VERSION 5.7 ;
  NOWIREEXTENSIONATPIN ON ;
  DIVIDERCHAR "/" ;
  BUSBITCHARS "[]" ;
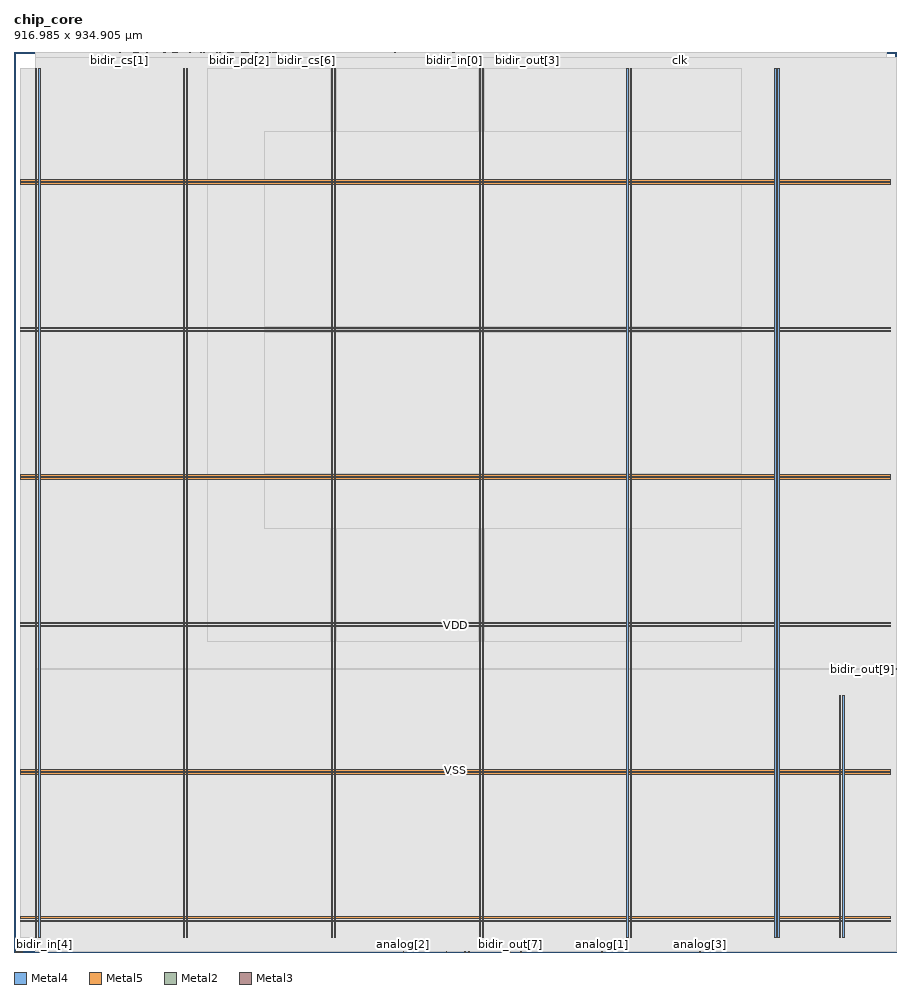
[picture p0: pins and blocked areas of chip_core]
MACRO chip_core
  CLASS BLOCK ;
  FOREIGN chip_core ;
  ORIGIN 0.000 0.000 ;
  SIZE 916.985 BY 934.905 ;
  PIN VDD
    DIRECTION INOUT ;
    USE POWER ;
    PORT
      LAYER Metal4 ;
        RECT 22.240 15.380 23.840 917.580 ;
    END
    PORT
      LAYER Metal4 ;
        RECT 175.840 15.380 177.440 917.580 ;
    END
    PORT
      LAYER Metal4 ;
        RECT 329.440 15.380 331.040 917.580 ;
    END
    PORT
      LAYER Metal4 ;
        RECT 483.040 15.380 484.640 917.580 ;
    END
    PORT
      LAYER Metal4 ;
        RECT 636.640 15.380 638.240 917.580 ;
    END
    PORT
      LAYER Metal4 ;
        RECT 790.240 15.380 791.840 917.580 ;
    END
    PORT
      LAYER Metal5 ;
        RECT 6.720 31.530 910.000 33.130 ;
    END
    PORT
      LAYER Metal5 ;
        RECT 6.720 184.710 910.000 186.310 ;
    END
    PORT
      LAYER Metal5 ;
        RECT 6.720 337.890 910.000 339.490 ;
    END
    PORT
      LAYER Metal5 ;
        RECT 6.720 491.070 910.000 492.670 ;
    END
    PORT
      LAYER Metal5 ;
        RECT 6.720 644.250 910.000 645.850 ;
    END
    PORT
      LAYER Metal5 ;
        RECT 6.720 797.430 910.000 799.030 ;
    END
    PORT
      LAYER Metal4 ;
        RECT 857.400 15.380 859.000 266.860 ;
    END
  END VDD
  PIN VSS
    DIRECTION INOUT ;
    USE GROUND ;
    PORT
      LAYER Metal4 ;
        RECT 25.540 15.380 27.140 917.580 ;
    END
    PORT
      LAYER Metal4 ;
        RECT 179.140 15.380 180.740 917.580 ;
    END
    PORT
      LAYER Metal4 ;
        RECT 332.740 15.380 334.340 917.580 ;
    END
    PORT
      LAYER Metal4 ;
        RECT 486.340 15.380 487.940 917.580 ;
    END
    PORT
      LAYER Metal4 ;
        RECT 639.940 15.380 641.540 917.580 ;
    END
    PORT
      LAYER Metal4 ;
        RECT 793.540 15.380 795.140 917.580 ;
    END
    PORT
      LAYER Metal5 ;
        RECT 6.720 34.830 910.000 36.430 ;
    END
    PORT
      LAYER Metal5 ;
        RECT 6.720 188.010 910.000 189.610 ;
    END
    PORT
      LAYER Metal5 ;
        RECT 6.720 341.190 910.000 342.790 ;
    END
    PORT
      LAYER Metal5 ;
        RECT 6.720 494.370 910.000 495.970 ;
    END
    PORT
      LAYER Metal5 ;
        RECT 6.720 647.550 910.000 649.150 ;
    END
    PORT
      LAYER Metal5 ;
        RECT 6.720 800.730 910.000 802.330 ;
    END
    PORT
      LAYER Metal4 ;
        RECT 860.760 15.380 862.360 266.860 ;
    END
  END VSS
  PIN analog[0]
    DIRECTION INOUT ;
    USE SIGNAL ;
    ANTENNAGATEAREA 0.741000 ;
    PORT
      LAYER Metal2 ;
        RECT 507.360 0.000 507.920 0.560 ;
    END
  END analog[0]
  PIN analog[1]
    DIRECTION INOUT ;
    USE SIGNAL ;
    ANTENNAGATEAREA 0.741000 ;
    PORT
      LAYER Metal2 ;
        RECT 610.400 0.000 610.960 0.560 ;
    END
  END analog[1]
  PIN analog[2]
    DIRECTION INOUT ;
    USE SIGNAL ;
    PORT
      LAYER Metal2 ;
        RECT 404.320 0.000 404.880 0.560 ;
    END
  END analog[2]
  PIN analog[3]
    DIRECTION INOUT ;
    USE SIGNAL ;
    ANTENNAGATEAREA 0.741000 ;
    PORT
      LAYER Metal2 ;
        RECT 712.320 0.000 712.880 0.560 ;
    END
  END analog[3]
  PIN bidir_cs[0]
    DIRECTION OUTPUT ;
    USE SIGNAL ;
    ANTENNADIFFAREA 0.536800 ;
    PORT
      LAYER Metal2 ;
        RECT 125.440 934.345 126.000 934.905 ;
    END
  END bidir_cs[0]
  PIN bidir_cs[1]
    DIRECTION OUTPUT ;
    USE SIGNAL ;
    ANTENNADIFFAREA 0.536800 ;
    PORT
      LAYER Metal2 ;
        RECT 109.760 934.345 110.320 934.905 ;
    END
  END bidir_cs[1]
  PIN bidir_cs[2]
    DIRECTION OUTPUT ;
    USE SIGNAL ;
    ANTENNADIFFAREA 0.536800 ;
    PORT
      LAYER Metal2 ;
        RECT 133.280 934.345 133.840 934.905 ;
    END
  END bidir_cs[2]
  PIN bidir_cs[3]
    DIRECTION OUTPUT ;
    USE SIGNAL ;
    ANTENNADIFFAREA 0.360800 ;
    PORT
      LAYER Metal2 ;
        RECT 229.600 934.345 230.160 934.905 ;
    END
  END bidir_cs[3]
  PIN bidir_cs[4]
    DIRECTION OUTPUT ;
    USE SIGNAL ;
    ANTENNADIFFAREA 0.360800 ;
    PORT
      LAYER Metal2 ;
        RECT 231.840 934.345 232.400 934.905 ;
    END
  END bidir_cs[4]
  PIN bidir_cs[5]
    DIRECTION OUTPUT ;
    USE SIGNAL ;
    ANTENNADIFFAREA 0.360800 ;
    PORT
      LAYER Metal2 ;
        RECT 155.680 934.345 156.240 934.905 ;
    END
  END bidir_cs[5]
  PIN bidir_cs[6]
    DIRECTION OUTPUT ;
    USE SIGNAL ;
    ANTENNADIFFAREA 0.360800 ;
    PORT
      LAYER Metal2 ;
        RECT 303.520 934.345 304.080 934.905 ;
    END
  END bidir_cs[6]
  PIN bidir_cs[7]
    DIRECTION OUTPUT ;
    USE SIGNAL ;
    ANTENNADIFFAREA 0.360800 ;
    PORT
      LAYER Metal2 ;
        RECT 131.040 934.345 131.600 934.905 ;
    END
  END bidir_cs[7]
  PIN bidir_cs[8]
    DIRECTION OUTPUT ;
    USE SIGNAL ;
    ANTENNADIFFAREA 0.360800 ;
    PORT
      LAYER Metal2 ;
        RECT 226.240 934.345 226.800 934.905 ;
    END
  END bidir_cs[8]
  PIN bidir_cs[9]
    DIRECTION OUTPUT ;
    USE SIGNAL ;
    ANTENNADIFFAREA 0.360800 ;
    PORT
      LAYER Metal2 ;
        RECT 241.920 934.345 242.480 934.905 ;
    END
  END bidir_cs[9]
  PIN bidir_ie[0]
    DIRECTION OUTPUT ;
    USE SIGNAL ;
    ANTENNADIFFAREA 0.536800 ;
    PORT
      LAYER Metal2 ;
        RECT 265.440 934.345 266.000 934.905 ;
    END
  END bidir_ie[0]
  PIN bidir_ie[1]
    DIRECTION OUTPUT ;
    USE SIGNAL ;
    ANTENNADIFFAREA 0.536800 ;
    PORT
      LAYER Metal2 ;
        RECT 169.120 934.345 169.680 934.905 ;
    END
  END bidir_ie[1]
  PIN bidir_ie[2]
    DIRECTION OUTPUT ;
    USE SIGNAL ;
    ANTENNADIFFAREA 0.536800 ;
    PORT
      LAYER Metal2 ;
        RECT 213.920 934.345 214.480 934.905 ;
    END
  END bidir_ie[2]
  PIN bidir_ie[3]
    DIRECTION OUTPUT ;
    USE SIGNAL ;
    ANTENNADIFFAREA 0.360800 ;
    PORT
      LAYER Metal2 ;
        RECT 236.320 934.345 236.880 934.905 ;
    END
  END bidir_ie[3]
  PIN bidir_ie[4]
    DIRECTION OUTPUT ;
    USE SIGNAL ;
    ANTENNADIFFAREA 0.360800 ;
    PORT
      LAYER Metal2 ;
        RECT 232.960 934.345 233.520 934.905 ;
    END
  END bidir_ie[4]
  PIN bidir_ie[5]
    DIRECTION OUTPUT ;
    USE SIGNAL ;
    ANTENNADIFFAREA 0.360800 ;
    PORT
      LAYER Metal2 ;
        RECT 197.120 934.345 197.680 934.905 ;
    END
  END bidir_ie[5]
  PIN bidir_ie[6]
    DIRECTION OUTPUT ;
    USE SIGNAL ;
    ANTENNADIFFAREA 0.360800 ;
    PORT
      LAYER Metal2 ;
        RECT 161.280 934.345 161.840 934.905 ;
    END
  END bidir_ie[6]
  PIN bidir_ie[7]
    DIRECTION OUTPUT ;
    USE SIGNAL ;
    ANTENNADIFFAREA 0.360800 ;
    PORT
      LAYER Metal2 ;
        RECT 235.200 934.345 235.760 934.905 ;
    END
  END bidir_ie[7]
  PIN bidir_ie[8]
    DIRECTION OUTPUT ;
    USE SIGNAL ;
    ANTENNADIFFAREA 0.360800 ;
    PORT
      LAYER Metal2 ;
        RECT 268.800 934.345 269.360 934.905 ;
    END
  END bidir_ie[8]
  PIN bidir_ie[9]
    DIRECTION OUTPUT ;
    USE SIGNAL ;
    ANTENNADIFFAREA 0.360800 ;
    PORT
      LAYER Metal2 ;
        RECT 272.160 934.345 272.720 934.905 ;
    END
  END bidir_ie[9]
  PIN bidir_in[0]
    DIRECTION INPUT ;
    USE SIGNAL ;
    ANTENNAGATEAREA 0.498500 ;
    PORT
      LAYER Metal2 ;
        RECT 456.960 934.345 457.520 934.905 ;
    END
  END bidir_in[0]
  PIN bidir_in[1]
    DIRECTION INPUT ;
    USE SIGNAL ;
    ANTENNAGATEAREA 0.498500 ;
    PORT
      LAYER Metal2 ;
        RECT 455.840 934.345 456.400 934.905 ;
    END
  END bidir_in[1]
  PIN bidir_in[2]
    DIRECTION INPUT ;
    USE SIGNAL ;
    ANTENNAGATEAREA 0.498500 ;
    PORT
      LAYER Metal2 ;
        RECT 395.360 934.345 395.920 934.905 ;
    END
  END bidir_in[2]
  PIN bidir_in[3]
    DIRECTION INPUT ;
    USE SIGNAL ;
    PORT
      LAYER Metal2 ;
        RECT 1.120 0.000 1.680 0.560 ;
    END
  END bidir_in[3]
  PIN bidir_in[4]
    DIRECTION INPUT ;
    USE SIGNAL ;
    PORT
      LAYER Metal2 ;
        RECT 2.240 0.000 2.800 0.560 ;
    END
  END bidir_in[4]
  PIN bidir_in[5]
    DIRECTION INPUT ;
    USE SIGNAL ;
    PORT
      LAYER Metal2 ;
        RECT 3.360 0.000 3.920 0.560 ;
    END
  END bidir_in[5]
  PIN bidir_in[6]
    DIRECTION INPUT ;
    USE SIGNAL ;
    PORT
      LAYER Metal2 ;
        RECT 4.480 0.000 5.040 0.560 ;
    END
  END bidir_in[6]
  PIN bidir_in[7]
    DIRECTION INPUT ;
    USE SIGNAL ;
    PORT
      LAYER Metal2 ;
        RECT 5.600 0.000 6.160 0.560 ;
    END
  END bidir_in[7]
  PIN bidir_in[8]
    DIRECTION INPUT ;
    USE SIGNAL ;
    PORT
      LAYER Metal2 ;
        RECT 6.720 0.000 7.280 0.560 ;
    END
  END bidir_in[8]
  PIN bidir_in[9]
    DIRECTION INPUT ;
    USE SIGNAL ;
    PORT
      LAYER Metal2 ;
        RECT 7.840 0.000 8.400 0.560 ;
    END
  END bidir_in[9]
  PIN bidir_oe[0]
    DIRECTION OUTPUT ;
    USE SIGNAL ;
    ANTENNADIFFAREA 0.360800 ;
    PORT
      LAYER Metal2 ;
        RECT 263.200 934.345 263.760 934.905 ;
    END
  END bidir_oe[0]
  PIN bidir_oe[1]
    DIRECTION OUTPUT ;
    USE SIGNAL ;
    ANTENNADIFFAREA 0.360800 ;
    PORT
      LAYER Metal2 ;
        RECT 276.640 934.345 277.200 934.905 ;
    END
  END bidir_oe[1]
  PIN bidir_oe[2]
    DIRECTION OUTPUT ;
    USE SIGNAL ;
    ANTENNADIFFAREA 0.360800 ;
    PORT
      LAYER Metal2 ;
        RECT 274.400 934.345 274.960 934.905 ;
    END
  END bidir_oe[2]
  PIN bidir_oe[3]
    DIRECTION OUTPUT ;
    USE SIGNAL ;
    ANTENNADIFFAREA 1.182800 ;
    PORT
      LAYER Metal2 ;
        RECT 520.800 934.345 521.360 934.905 ;
    END
  END bidir_oe[3]
  PIN bidir_oe[4]
    DIRECTION OUTPUT ;
    USE SIGNAL ;
    ANTENNADIFFAREA 0.536800 ;
    PORT
      LAYER Metal2 ;
        RECT 243.040 934.345 243.600 934.905 ;
    END
  END bidir_oe[4]
  PIN bidir_oe[5]
    DIRECTION OUTPUT ;
    USE SIGNAL ;
    ANTENNADIFFAREA 0.536800 ;
    PORT
      LAYER Metal2 ;
        RECT 182.560 934.345 183.120 934.905 ;
    END
  END bidir_oe[5]
  PIN bidir_oe[6]
    DIRECTION OUTPUT ;
    USE SIGNAL ;
    ANTENNADIFFAREA 0.536800 ;
    PORT
      LAYER Metal2 ;
        RECT 191.520 934.345 192.080 934.905 ;
    END
  END bidir_oe[6]
  PIN bidir_oe[7]
    DIRECTION OUTPUT ;
    USE SIGNAL ;
    ANTENNADIFFAREA 0.536800 ;
    PORT
      LAYER Metal2 ;
        RECT 168.000 934.345 168.560 934.905 ;
    END
  END bidir_oe[7]
  PIN bidir_oe[8]
    DIRECTION OUTPUT ;
    USE SIGNAL ;
    ANTENNADIFFAREA 0.536800 ;
    PORT
      LAYER Metal2 ;
        RECT 275.520 934.345 276.080 934.905 ;
    END
  END bidir_oe[8]
  PIN bidir_oe[9]
    DIRECTION OUTPUT ;
    USE SIGNAL ;
    ANTENNADIFFAREA 0.536800 ;
    PORT
      LAYER Metal2 ;
        RECT 160.160 934.345 160.720 934.905 ;
    END
  END bidir_oe[9]
  PIN bidir_out[0]
    DIRECTION OUTPUT ;
    USE SIGNAL ;
    ANTENNADIFFAREA 1.182800 ;
    PORT
      LAYER Metal2 ;
        RECT 224.000 934.345 224.560 934.905 ;
    END
  END bidir_out[0]
  PIN bidir_out[1]
    DIRECTION OUTPUT ;
    USE SIGNAL ;
    ANTENNADIFFAREA 1.182800 ;
    PORT
      LAYER Metal2 ;
        RECT 221.760 934.345 222.320 934.905 ;
    END
  END bidir_out[1]
  PIN bidir_out[2]
    DIRECTION OUTPUT ;
    USE SIGNAL ;
    ANTENNADIFFAREA 1.182800 ;
    PORT
      LAYER Metal2 ;
        RECT 220.640 934.345 221.200 934.905 ;
    END
  END bidir_out[2]
  PIN bidir_out[3]
    DIRECTION OUTPUT ;
    USE SIGNAL ;
    ANTENNADIFFAREA 1.182800 ;
    PORT
      LAYER Metal2 ;
        RECT 533.120 934.345 533.680 934.905 ;
    END
  END bidir_out[3]
  PIN bidir_out[4]
    DIRECTION OUTPUT ;
    USE SIGNAL ;
    ANTENNADIFFAREA 1.182800 ;
    PORT
      LAYER Metal2 ;
        RECT 472.640 0.000 473.200 0.560 ;
    END
  END bidir_out[4]
  PIN bidir_out[5]
    DIRECTION OUTPUT ;
    USE SIGNAL ;
    ANTENNADIFFAREA 1.182800 ;
    PORT
      LAYER Metal2 ;
        RECT 468.160 0.000 468.720 0.560 ;
    END
  END bidir_out[5]
  PIN bidir_out[6]
    DIRECTION OUTPUT ;
    USE SIGNAL ;
    ANTENNADIFFAREA 1.182800 ;
    PORT
      LAYER Metal2 ;
        RECT 526.400 0.000 526.960 0.560 ;
    END
  END bidir_out[6]
  PIN bidir_out[7]
    DIRECTION OUTPUT ;
    USE SIGNAL ;
    ANTENNADIFFAREA 1.182800 ;
    PORT
      LAYER Metal2 ;
        RECT 515.200 0.000 515.760 0.560 ;
    END
  END bidir_out[7]
  PIN bidir_out[8]
    DIRECTION OUTPUT ;
    USE SIGNAL ;
    ANTENNADIFFAREA 1.182800 ;
    PORT
      LAYER Metal2 ;
        RECT 449.120 0.000 449.680 0.560 ;
    END
  END bidir_out[8]
  PIN bidir_out[9]
    DIRECTION OUTPUT ;
    USE SIGNAL ;
    ANTENNADIFFAREA 1.182800 ;
    PORT
      LAYER Metal3 ;
        RECT 916.425 293.440 916.985 294.000 ;
    END
  END bidir_out[9]
  PIN bidir_pd[0]
    DIRECTION OUTPUT ;
    USE SIGNAL ;
    ANTENNADIFFAREA 0.360800 ;
    PORT
      LAYER Metal2 ;
        RECT 157.920 934.345 158.480 934.905 ;
    END
  END bidir_pd[0]
  PIN bidir_pd[1]
    DIRECTION OUTPUT ;
    USE SIGNAL ;
    ANTENNADIFFAREA 0.360800 ;
    PORT
      LAYER Metal2 ;
        RECT 246.400 934.345 246.960 934.905 ;
    END
  END bidir_pd[1]
  PIN bidir_pd[2]
    DIRECTION OUTPUT ;
    USE SIGNAL ;
    ANTENNADIFFAREA 0.360800 ;
    PORT
      LAYER Metal2 ;
        RECT 234.080 934.345 234.640 934.905 ;
    END
  END bidir_pd[2]
  PIN bidir_pd[3]
    DIRECTION OUTPUT ;
    USE SIGNAL ;
    ANTENNADIFFAREA 0.360800 ;
    PORT
      LAYER Metal2 ;
        RECT 249.760 934.345 250.320 934.905 ;
    END
  END bidir_pd[3]
  PIN bidir_pd[4]
    DIRECTION OUTPUT ;
    USE SIGNAL ;
    ANTENNADIFFAREA 0.360800 ;
    PORT
      LAYER Metal2 ;
        RECT 124.320 934.345 124.880 934.905 ;
    END
  END bidir_pd[4]
  PIN bidir_pd[5]
    DIRECTION OUTPUT ;
    USE SIGNAL ;
    ANTENNADIFFAREA 0.360800 ;
    PORT
      LAYER Metal2 ;
        RECT 165.760 934.345 166.320 934.905 ;
    END
  END bidir_pd[5]
  PIN bidir_pd[6]
    DIRECTION OUTPUT ;
    USE SIGNAL ;
    ANTENNADIFFAREA 0.360800 ;
    PORT
      LAYER Metal2 ;
        RECT 137.760 934.345 138.320 934.905 ;
    END
  END bidir_pd[6]
  PIN bidir_pd[7]
    DIRECTION OUTPUT ;
    USE SIGNAL ;
    ANTENNADIFFAREA 0.360800 ;
    PORT
      LAYER Metal2 ;
        RECT 250.880 934.345 251.440 934.905 ;
    END
  END bidir_pd[7]
  PIN bidir_pd[8]
    DIRECTION OUTPUT ;
    USE SIGNAL ;
    ANTENNADIFFAREA 0.360800 ;
    PORT
      LAYER Metal2 ;
        RECT 164.640 934.345 165.200 934.905 ;
    END
  END bidir_pd[8]
  PIN bidir_pd[9]
    DIRECTION OUTPUT ;
    USE SIGNAL ;
    ANTENNADIFFAREA 0.360800 ;
    PORT
      LAYER Metal2 ;
        RECT 127.680 934.345 128.240 934.905 ;
    END
  END bidir_pd[9]
  PIN bidir_pu[0]
    DIRECTION OUTPUT ;
    USE SIGNAL ;
    ANTENNADIFFAREA 0.536800 ;
    PORT
      LAYER Metal2 ;
        RECT 210.560 934.345 211.120 934.905 ;
    END
  END bidir_pu[0]
  PIN bidir_pu[1]
    DIRECTION OUTPUT ;
    USE SIGNAL ;
    ANTENNADIFFAREA 0.360800 ;
    PORT
      LAYER Metal2 ;
        RECT 162.400 934.345 162.960 934.905 ;
    END
  END bidir_pu[1]
  PIN bidir_pu[2]
    DIRECTION OUTPUT ;
    USE SIGNAL ;
    ANTENNADIFFAREA 0.360800 ;
    PORT
      LAYER Metal2 ;
        RECT 269.920 934.345 270.480 934.905 ;
    END
  END bidir_pu[2]
  PIN bidir_pu[3]
    DIRECTION OUTPUT ;
    USE SIGNAL ;
    ANTENNADIFFAREA 0.360800 ;
    PORT
      LAYER Metal2 ;
        RECT 252.000 934.345 252.560 934.905 ;
    END
  END bidir_pu[3]
  PIN bidir_pu[4]
    DIRECTION OUTPUT ;
    USE SIGNAL ;
    ANTENNADIFFAREA 0.360800 ;
    PORT
      LAYER Metal2 ;
        RECT 128.800 934.345 129.360 934.905 ;
    END
  END bidir_pu[4]
  PIN bidir_pu[5]
    DIRECTION OUTPUT ;
    USE SIGNAL ;
    ANTENNADIFFAREA 0.360800 ;
    PORT
      LAYER Metal2 ;
        RECT 193.760 934.345 194.320 934.905 ;
    END
  END bidir_pu[5]
  PIN bidir_pu[6]
    DIRECTION OUTPUT ;
    USE SIGNAL ;
    ANTENNADIFFAREA 0.360800 ;
    PORT
      LAYER Metal2 ;
        RECT 216.160 934.345 216.720 934.905 ;
    END
  END bidir_pu[6]
  PIN bidir_pu[7]
    DIRECTION OUTPUT ;
    USE SIGNAL ;
    ANTENNADIFFAREA 0.360800 ;
    PORT
      LAYER Metal2 ;
        RECT 156.800 934.345 157.360 934.905 ;
    END
  END bidir_pu[7]
  PIN bidir_pu[8]
    DIRECTION OUTPUT ;
    USE SIGNAL ;
    ANTENNADIFFAREA 0.360800 ;
    PORT
      LAYER Metal2 ;
        RECT 163.520 934.345 164.080 934.905 ;
    END
  END bidir_pu[8]
  PIN bidir_pu[9]
    DIRECTION OUTPUT ;
    USE SIGNAL ;
    ANTENNADIFFAREA 0.360800 ;
    PORT
      LAYER Metal2 ;
        RECT 222.880 934.345 223.440 934.905 ;
    END
  END bidir_pu[9]
  PIN bidir_sl[0]
    DIRECTION OUTPUT ;
    USE SIGNAL ;
    ANTENNADIFFAREA 0.360800 ;
    PORT
      LAYER Metal2 ;
        RECT 166.880 934.345 167.440 934.905 ;
    END
  END bidir_sl[0]
  PIN bidir_sl[1]
    DIRECTION OUTPUT ;
    USE SIGNAL ;
    ANTENNADIFFAREA 0.360800 ;
    PORT
      LAYER Metal2 ;
        RECT 239.680 934.345 240.240 934.905 ;
    END
  END bidir_sl[1]
  PIN bidir_sl[2]
    DIRECTION OUTPUT ;
    USE SIGNAL ;
    ANTENNADIFFAREA 0.360800 ;
    PORT
      LAYER Metal2 ;
        RECT 320.320 934.345 320.880 934.905 ;
    END
  END bidir_sl[2]
  PIN bidir_sl[3]
    DIRECTION OUTPUT ;
    USE SIGNAL ;
    ANTENNADIFFAREA 0.536800 ;
    PORT
      LAYER Metal2 ;
        RECT 238.560 934.345 239.120 934.905 ;
    END
  END bidir_sl[3]
  PIN bidir_sl[4]
    DIRECTION OUTPUT ;
    USE SIGNAL ;
    ANTENNADIFFAREA 0.360800 ;
    PORT
      LAYER Metal2 ;
        RECT 159.040 934.345 159.600 934.905 ;
    END
  END bidir_sl[4]
  PIN bidir_sl[5]
    DIRECTION OUTPUT ;
    USE SIGNAL ;
    ANTENNADIFFAREA 0.360800 ;
    PORT
      LAYER Metal2 ;
        RECT 240.800 934.345 241.360 934.905 ;
    END
  END bidir_sl[5]
  PIN bidir_sl[6]
    DIRECTION OUTPUT ;
    USE SIGNAL ;
    ANTENNADIFFAREA 0.360800 ;
    PORT
      LAYER Metal2 ;
        RECT 273.280 934.345 273.840 934.905 ;
    END
  END bidir_sl[6]
  PIN bidir_sl[7]
    DIRECTION OUTPUT ;
    USE SIGNAL ;
    ANTENNADIFFAREA 0.360800 ;
    PORT
      LAYER Metal2 ;
        RECT 129.920 934.345 130.480 934.905 ;
    END
  END bidir_sl[7]
  PIN bidir_sl[8]
    DIRECTION OUTPUT ;
    USE SIGNAL ;
    ANTENNADIFFAREA 0.360800 ;
    PORT
      LAYER Metal2 ;
        RECT 227.360 934.345 227.920 934.905 ;
    END
  END bidir_sl[8]
  PIN bidir_sl[9]
    DIRECTION OUTPUT ;
    USE SIGNAL ;
    ANTENNADIFFAREA 0.360800 ;
    PORT
      LAYER Metal2 ;
        RECT 225.120 934.345 225.680 934.905 ;
    END
  END bidir_sl[9]
  PIN clk
    DIRECTION INPUT ;
    USE SIGNAL ;
    ANTENNAGATEAREA 9.476000 ;
    PORT
      LAYER Metal2 ;
        RECT 691.040 934.345 691.600 934.905 ;
    END
  END clk
  PIN input_in
    DIRECTION INPUT ;
    USE SIGNAL ;
    ANTENNAGATEAREA 0.498500 ;
    PORT
      LAYER Metal2 ;
        RECT 218.400 934.345 218.960 934.905 ;
    END
  END input_in
  PIN input_pd
    DIRECTION OUTPUT ;
    USE SIGNAL ;
    ANTENNADIFFAREA 0.360800 ;
    PORT
      LAYER Metal2 ;
        RECT 237.440 934.345 238.000 934.905 ;
    END
  END input_pd
  PIN input_pu
    DIRECTION OUTPUT ;
    USE SIGNAL ;
    ANTENNADIFFAREA 0.360800 ;
    PORT
      LAYER Metal2 ;
        RECT 118.720 934.345 119.280 934.905 ;
    END
  END input_pu
  PIN rst_n
    DIRECTION INPUT ;
    USE SIGNAL ;
    ANTENNAGATEAREA 1.102000 ;
    PORT
      LAYER Metal2 ;
        RECT 689.920 934.345 690.480 934.905 ;
    END
  END rst_n
  OBS
      LAYER Nwell ;
        RECT 6.290 15.250 910.430 917.710 ;
      LAYER Metal1 ;
        RECT 6.720 15.380 910.000 917.580 ;
      LAYER Metal2 ;
        RECT 22.380 934.045 109.460 934.765 ;
        RECT 110.620 934.045 118.420 934.765 ;
        RECT 119.580 934.045 124.020 934.765 ;
        RECT 126.300 934.045 127.380 934.765 ;
        RECT 131.900 934.045 132.980 934.765 ;
        RECT 134.140 934.045 137.460 934.765 ;
        RECT 138.620 934.045 155.380 934.765 ;
        RECT 169.980 934.045 182.260 934.765 ;
        RECT 183.420 934.045 191.220 934.765 ;
        RECT 192.380 934.045 193.460 934.765 ;
        RECT 194.620 934.045 196.820 934.765 ;
        RECT 197.980 934.045 210.260 934.765 ;
        RECT 211.420 934.045 213.620 934.765 ;
        RECT 214.780 934.045 215.860 934.765 ;
        RECT 217.020 934.045 218.100 934.765 ;
        RECT 219.260 934.045 220.340 934.765 ;
        RECT 228.220 934.045 229.300 934.765 ;
        RECT 230.460 934.045 231.540 934.765 ;
        RECT 243.900 934.045 246.100 934.765 ;
        RECT 247.260 934.045 249.460 934.765 ;
        RECT 252.860 934.045 262.900 934.765 ;
        RECT 264.060 934.045 265.140 934.765 ;
        RECT 266.300 934.045 268.500 934.765 ;
        RECT 270.780 934.045 271.860 934.765 ;
        RECT 277.500 934.045 303.220 934.765 ;
        RECT 304.380 934.045 320.020 934.765 ;
        RECT 321.180 934.045 395.060 934.765 ;
        RECT 396.220 934.045 455.540 934.765 ;
        RECT 457.820 934.045 520.500 934.765 ;
        RECT 521.660 934.045 532.820 934.765 ;
        RECT 533.980 934.045 689.620 934.765 ;
        RECT 691.900 934.045 906.500 934.765 ;
        RECT 22.380 0.860 906.500 934.045 ;
        RECT 22.380 0.090 404.020 0.860 ;
        RECT 405.180 0.090 448.820 0.860 ;
        RECT 449.980 0.090 467.860 0.860 ;
        RECT 469.020 0.090 472.340 0.860 ;
        RECT 473.500 0.090 507.060 0.860 ;
        RECT 508.220 0.090 514.900 0.860 ;
        RECT 516.060 0.090 526.100 0.860 ;
        RECT 527.260 0.090 610.100 0.860 ;
        RECT 611.260 0.090 712.020 0.860 ;
        RECT 713.180 0.090 906.500 0.860 ;
      LAYER Metal3 ;
        RECT 22.330 294.300 916.425 929.460 ;
        RECT 22.330 293.140 916.125 294.300 ;
        RECT 22.330 0.140 916.425 293.140 ;
      LAYER Metal4 ;
        RECT 200.620 322.650 329.140 917.750 ;
        RECT 331.340 322.650 332.440 917.750 ;
        RECT 334.640 322.650 482.740 917.750 ;
        RECT 484.940 322.650 486.040 917.750 ;
        RECT 488.240 322.650 636.340 917.750 ;
        RECT 638.540 322.650 639.640 917.750 ;
        RECT 641.840 322.650 755.300 917.750 ;
      LAYER Metal5 ;
        RECT 260.460 802.930 755.380 852.070 ;
        RECT 260.460 799.630 755.380 800.130 ;
        RECT 260.460 649.750 755.380 796.830 ;
        RECT 260.460 646.450 755.380 646.950 ;
        RECT 260.460 496.570 755.380 643.650 ;
        RECT 260.460 493.270 755.380 493.770 ;
        RECT 260.460 440.330 755.380 490.470 ;
  END
END chip_core
END LIBRARY

